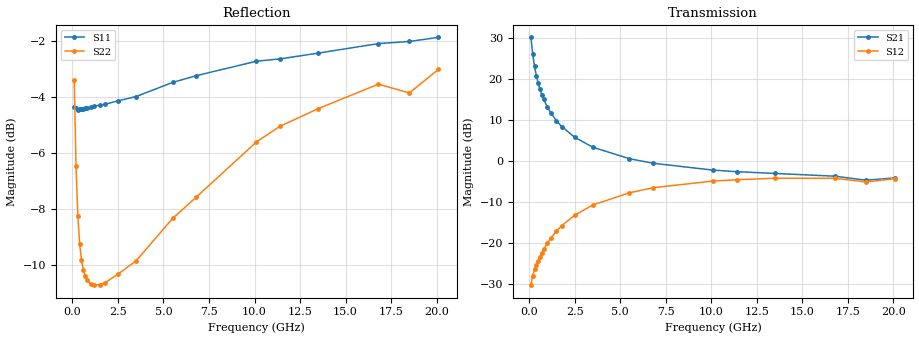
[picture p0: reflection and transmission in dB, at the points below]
!  Infineon Technologies AG
! BFR380L3 , PF131585-7, No.6, Th 09.10.01, soldered on pcb-board, measured with PP GSG850
!  Vce=0.5 V,  Ic=20.0 mA
! Common Emitter S-Parameters:  15. November 2001
#  GHz  S  MA  R  50
! f  S11  S21  S12  S22
! GHz  Mag  Ang  Mag  Ang  Mag  Ang  Mag  Ang
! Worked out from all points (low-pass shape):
!   201 points, 100 MHz to 20.1 GHz, reference 50 ohm
!   highest |S21| = 30.08 dB at 100 MHz (marker M1); lowest = -4.8 dB at 18.5 GHz (marker M2)
!   |S21| within 3 dB of the highest: start of sweep to 174.2 MHz
!   lowest |S11| = -4.5 dB at 300 MHz (marker M3), VSWR 3.98, Z = 13.5 - j13.4 ohm
!   |S11| at or under -10 dB: nowhere
!   |S22| runs from -10.7 to -3.0 dB; largest |S21 - S12| = 32
!   S11 on the Smith chart (normalised r, x): 100 MHz: 0.45, -0.85; 300 MHz: 0.27, -0.27; 1.8 GHz: 0.25, +0.16; 5.5 GHz: 0.28, +0.63; 11.4 GHz: 0.46, +1.37; 20.1 GHz: 0.91, +2.59
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0.1  0.6049 -92.6  31.93 132.4  0.03031 54.6  0.6757 -63.3
0.2  0.6031 -130.2  20.05 112.7  0.03971 48.3  0.4746 -96.0
0.3  0.5982 -147.8  14.2 103.6  0.04711 49.0  0.3857 -115.2
0.4  0.5985 -157.6  10.91 97.8  0.05346 51.0  0.344 -128.2
0.5  0.5987 -164.5  8.837 93.6  0.06035 53.7  0.322 -137.5
0.6  0.5991 -169.6  7.42 90.4  0.06762 55.5  0.3096 -144.6
0.7  0.6015 -173.9  6.402 87.5  0.07497 57.3  0.302 -150.2
0.8  0.6027 -177.3  5.626 85.0  0.08254 58.5  0.2969 -154.6
1  0.6038 177.0  4.54 80.7  0.09794 60.1  0.292 -161.5
1.2  0.6067 172.3  3.812 76.8  0.1138 60.8  0.2906 -166.7
1.5  0.609 166.3  3.082 71.5  0.1377 61.0  0.2911 -172.7
1.8  0.6113 160.8  2.6 66.6  0.1616 60.1  0.2936 -177.4
2.5  0.6199 149.4  1.936 56.2  0.2152 56.6  0.3039 173.8
3.5  0.6311 135.2  1.459 43.1  0.2881 50.0  0.3212 163.6
5.5  0.6686 112.2  1.059 22.6  0.4048 35.5  0.3822 145.3
6.8  0.6875 99.4  0.931 11.5  0.4671 26.0  0.4172 133.7
10.1  0.7296 75.9  0.7672 -8.3  0.5636 5.2  0.5234 110.0
11.4  0.7367 68.3  0.7341 -14.8  0.5851 -2.6  0.5584 101.0
13.5  0.7544 59.1  0.6985 -23.8  0.6105 -13.8  0.6004 88.0
16.8  0.7845 47.4  0.6462 -35.3  0.6093 -28.1  0.664 70.7
18.5  0.7914 45.3  0.5775 -42.4  0.5503 -36.0  0.6404 66.4
20.1  0.8048 38.4  0.6164 -45.7  0.6025 -40.6  0.7055 56.7
